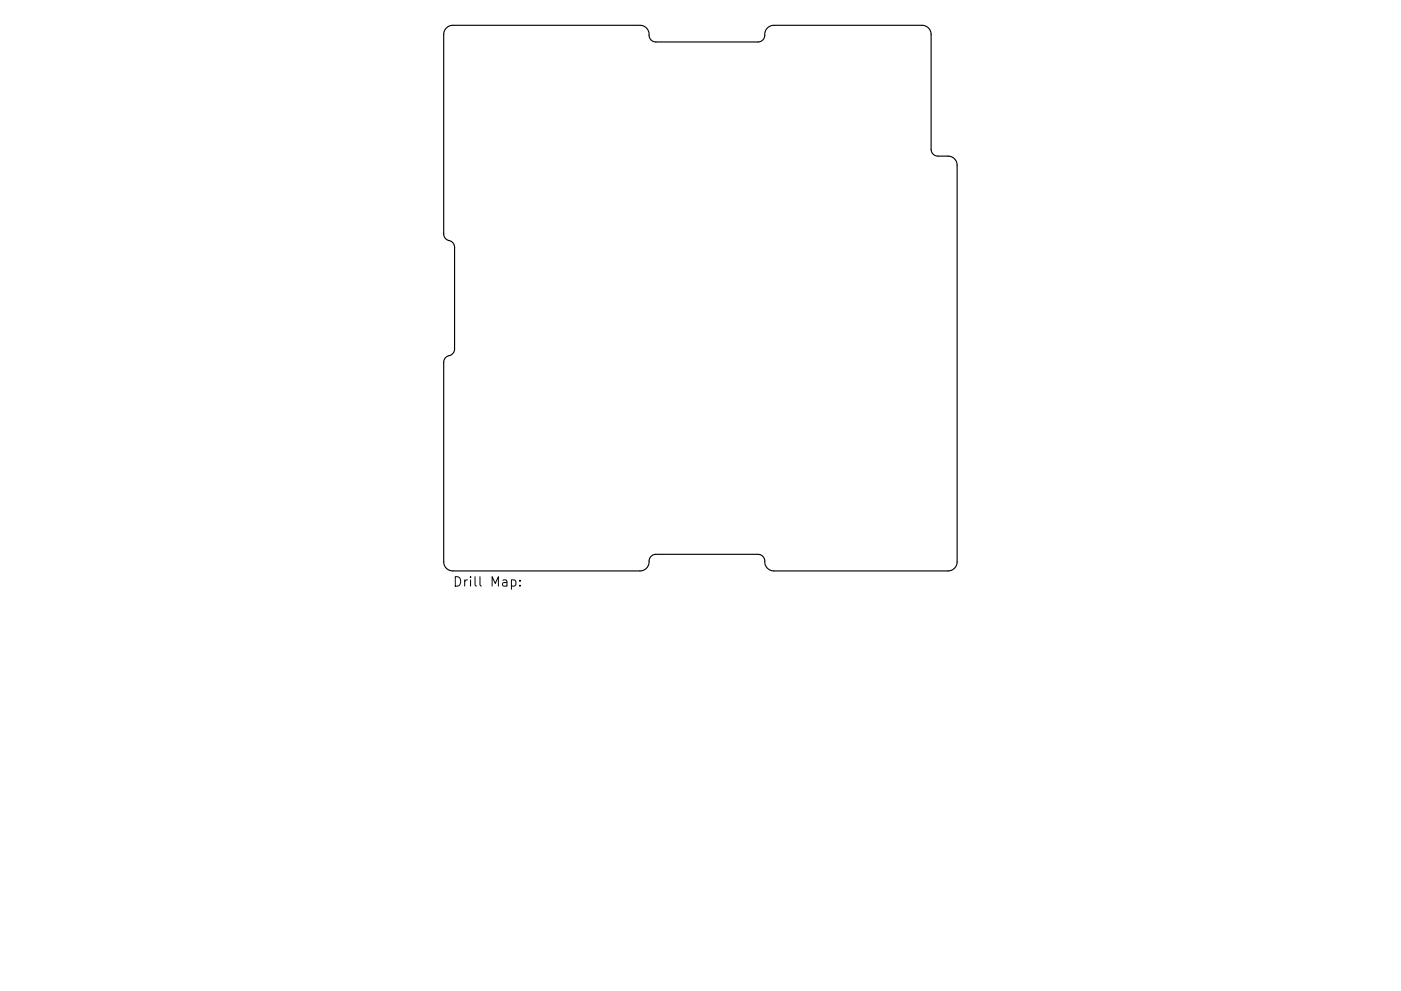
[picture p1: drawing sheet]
<svg xmlns="http://www.w3.org/2000/svg" width="297mm" height="210mm" viewBox="0 0 297 210" stroke-linecap="round" stroke-linejoin="round" font-family="sans-serif">
<defs><g id="words">
<text font-size="2.8" x="96" y="124.5">Drill Map:</text>
</g></defs>
<path d="M94.6 5.9l.7-.4 .7-.1h39.7a2.09 2.09 0 0 1 2 2.4l.4 .8 .8 .3h21.8a1.57 1.57 0 0 0 1.5-1.9 1.94 1.94 0 0 1 1.9-1.6h31.4a1.93 1.93 0 0 1 1.9 1.9v24.4a1.45 1.45 0 0 0 1.5 1.4h2.1a1.93 1.93 0 0 1 1.9 2v84.1a1.93 1.93 0 0 1-1.9 1.9h-36.9a2.09 2.09 0 0 1-2-2.4l-.5-.8-.8-.3h-21.7a1.57 1.57 0 0 0-1.5 1.9 1.94 1.94 0 0 1-1.9 1.6h-39.7a1.93 1.93 0 0 1-1.9-1.9v-42.3a1.73 1.73 0 0 1 1.6-1.6l.4-.5 .3-.7v-21.6a1.7 1.7 0 0 0-1.6-1.6l-.5-.5-.2-.8v-42.3l.1-.7z" fill="none" stroke="#000" stroke-width=".24"/>
<path d="M108.4 123.1l.6-.1 .4 .4v.6l-.2 .3h-.8M110.2 124.2v.2M110.2 123.1v.2" fill="none" stroke="#000" stroke-width=".21"/>
<use href="#words"/>
</svg>
